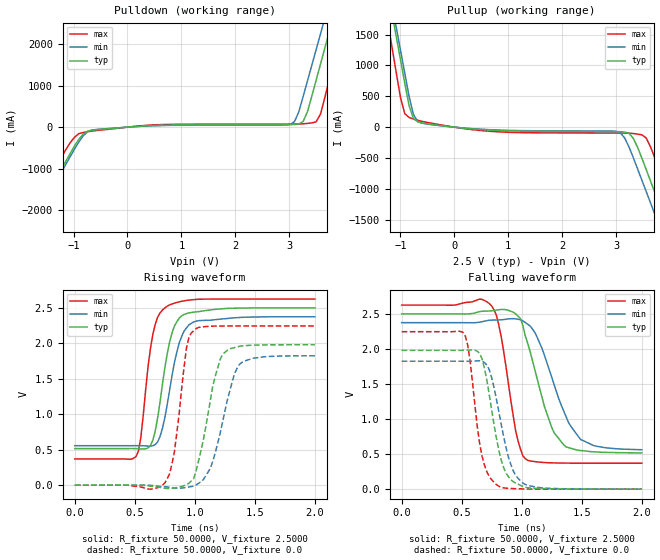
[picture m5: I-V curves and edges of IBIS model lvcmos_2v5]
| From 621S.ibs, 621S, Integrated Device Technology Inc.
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|   Model LVCMOS_2V5
[Model]   lvcmos_2v5
Model_type Output
Polarity   Non-Inverting
Vmeas =  1.2500V
Cref =   5.0000pF
Rref =   50.0000
Vref =   1.2500V
C_comp   2.0000pF   1.5000pF   2.5000pF
[Temperature Range]   55.0000   80.0000   -40.0000
[Voltage Range]   2.5000V   2.3750V   2.6250V
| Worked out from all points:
|   slope of the pulldown table from 0 to 0.375 V, typ, clamps not added: 11.7 ohm
|   slope of the pullup table from 0 to 0.375 V, typ, clamps not added: 12.2 ohm
|   rising waveform, R_fixture 50.0000, V_fixture 2.5000: 20-80 % time 117ps typ, 125ps min, 97.2ps max; typ from 0.516 V to 2.5 V
|   rising waveform, R_fixture 50.0000, V_fixture 0.0: 20-80 % time 140ps typ, 157ps min, 92.6ps max; typ from 0 V to 1.98 V
|   falling waveform, R_fixture 50.0000, V_fixture 2.5000: 20-80 % time 198ps typ, 232ps min, 122ps max; typ from 2.5 V to 0.517 V
|   falling waveform, R_fixture 50.0000, V_fixture 0.0: 20-80 % time 127ps typ, 139ps min, 101ps max; typ from 1.98 V to 0 V
[Pulldown]
|Voltage   I(typ)   I(min)   I(max)
-2.5V     -3.97A     -4.011A    -3.822A
-1.94V    -2.67A     -2.726A    -2.464A
-1.78V    -2.299A    -2.359A    -2.076A
-900mV    -287.5mA   -352.4mA   -156mA
-500mV    -52.68mA   -47.84mA   -71.7mA
3.02V     59.21mA    66.88mA    73.32mA
3.26V     135.9mA    739.5mA    80.51mA
3.5V      1.128A     1.864A     126.8mA
3.58V     1.512A     2.239A     308.1mA
3.74V     2.279A     2.988A     1.12A
3.98V     3.43A      4.113A     2.384A
4.94V     8.044A     8.622A     7.451A
[Pullup]
|Voltage   I(typ)   I(min)   I(max)
-2.44V    8.006A     8.005A     8.048A
-1.24V    2.249A     2.379A     1.735A
-1.08V    1.481A     1.628A     893.9mA
-920mV    713.3mA    877.6mA    218.9mA
-760mV    140.6mA    208.6mA    132.2mA
3V        -71.98mA   -68.07mA   -96.34mA
3.24V     -100.2mA   -319.6mA   -98.02mA
3.48V     -501.7mA   -860mA     -124.7mA
3.8V      -1.244A    -1.594A    -693.5mA
3.96V     -1.616A    -1.962A    -1.082A
4.2V      -2.174A    -2.513A    -1.665A
5V        -4.035A    -4.353A    -3.612A
[Ramp]
| variable   typ   min   max
dV/dt_r  1.1880/0.1401n   1.0944/0.1574n   1.3470/92.6376p
dV/dt_f  1.1896/0.1976n   1.0873/0.2315n   1.3529/0.1217n
R_load = 50.0000
[Rising Waveform]
R_fixture= 50.0000
V_fixture= 2.5000
V_fixture_min= 2.3750
V_fixture_max= 2.6250
|time   V(typ)   V(min)   V(max)
0s        515.8mV    556.7mV    369.9mV
510ps     515.6mV    556.9mV    402mV
550ps     511.8mV    556.6mV    671.7mV
610ps     525.2mV    550.7mV    1.667V
650ps     632.9mV    555.7mV    2.125V
710ps     1.171V     685.5mV    2.428V
770ps     1.852V     1.137V     2.523V
870ps     2.356V     2.006V     2.585V
970ps     2.434V     2.281V     2.613V
2ns       2.499V     2.374V     2.624V
[Rising Waveform]
R_fixture= 50.0000
V_fixture= 0.0
V_fixture_min= 0.0
V_fixture_max= 0.0
|time   V(typ)   V(min)   V(max)
0s        0V         0V         0V
750ps     -44.02mV   -21.94mV   30.95mV
830ps     -40.8mV    -42.03mV   470.1mV
930ps     8.199mV    -31.26mV   1.93V
1.01ns    199.8mV    2.515mV    2.207V
1.13ns    1.203V     241.8mV    2.24V
1.23ns    1.842V     882mV      2.244V
1.33ns    1.939V     1.57V      2.245V
1.39ns    1.963V     1.728V     2.245V
2ns       1.98V      1.824V     2.245V
[Falling Waveform]
R_fixture= 50.0000
V_fixture= 2.5000
V_fixture_min= 2.3750
V_fixture_max= 2.6250
|time   V(typ)   V(min)   V(max)
0s        2.5V       2.375V     2.625V
750ps     2.543V     2.411V     2.612V
830ps     2.563V     2.415V     2.169V
950ps     2.499V     2.429V     829.2mV
1.05ns    2.08V      2.352V     411.5mV
1.13ns    1.566V     2.162V     388.9mV
1.25ns    880.4mV    1.596V     375.7mV
1.35ns    631.9mV    1.114V     372.2mV
1.49ns    550.9mV    709.4mV    370.7mV
2ns       517.3mV    562.8mV    370.1mV
[Falling Waveform]
R_fixture= 50.0000
V_fixture= 0.0
V_fixture_min= 0.0
V_fixture_max= 0.0
|time   V(typ)   V(min)   V(max)
0s        1.98V      1.825V     2.246V
530ps     1.981V     1.824V     2.184V
570ps     1.985V     1.825V     1.83V
630ps     1.967V     1.83V      891.1mV
670ps     1.857V     1.824V     466.9mV
730ps     1.346V     1.703V     180.1mV
790ps     719.8mV    1.278V     64.12mV
890ps     177.8mV    452.4mV    12.02mV
1.01ns    38.98mV    86.8mV     3.654mV
2ns       155.3uV    273.5uV    87.23uV
